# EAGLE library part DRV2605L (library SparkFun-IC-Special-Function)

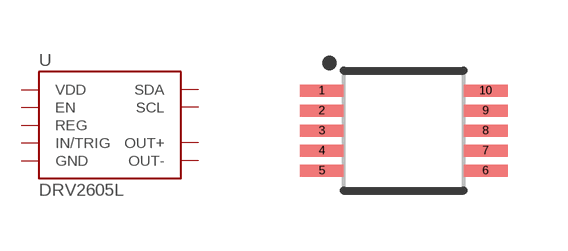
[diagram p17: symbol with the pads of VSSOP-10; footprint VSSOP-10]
Designator prefix U

## DRV2605L (PROD_ID: IC-13504)  [VSSOP-10]
1  REG
2  SCL
3  SDA
4  IN/TRIG
5  EN
6  VDD
7  OUT+
8  GND
9  OUT-
10  VDD

## Footprint VSSOP-10 (pad centres in mm)
smd 1.1 x 0.3: 1 -2.05,1; 2 -2.05,0.5; 3 -2.05,0; 4 -2.05,-0.5; 5 -2.05,-1; 6 2.05,-1; 7 2.05,-0.5; 8 2.05,0; 9 2.05,0.5; 10 2.05,1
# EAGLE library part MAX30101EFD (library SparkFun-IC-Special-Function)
MAX30101 High-Sensitivity Pulse Oximeter and Heart-Rate Sensor The MAX30101 is an integrated pulse oximetry and heart-rate monitor module. It includes internal LEDs, photodetectors, optical elements, and low-noise electronics with ambient light rejection. The MAX30101 provides a complete system solution to ease the design-in process for mobile and wearable devices. The MAX30101 operates on a single 1.8V power supply and a separate 5.0V power supply for the internal LEDs. Communication is through a standard I2C-compatible interface. The module can be shut down through software with zero standby current, allowing the power rails to remain powered at all times

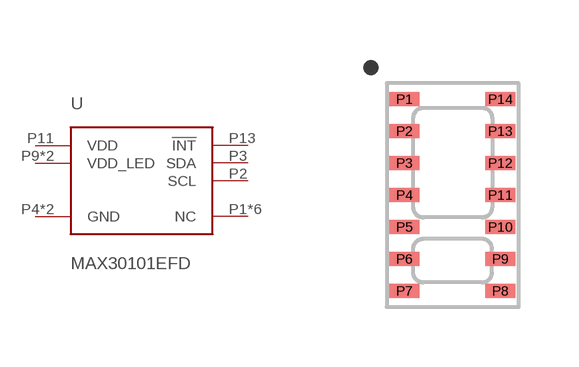
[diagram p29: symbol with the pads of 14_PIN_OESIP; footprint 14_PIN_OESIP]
Designator prefix U

## MAX30101EFD (PROD_ID: IC-14270)  [14_PIN_OESIP]
P1  NC  nc
P2  SCL
P3  SDA
P4  GND  pwr
P5  NC  nc
P6  NC  nc
P7  NC  nc
P8  NC  nc
P9  VDD_LED  pwr
P10  VDD_LED  pwr
P11  VDD  pwr
P12  GND  pwr
P13  !INT
P14  NC  nc

## Footprint 14_PIN_OESIP (pad centres in mm)
MAX30101 14 Pin OESIP Phycial Characteristics: 3.3 X 5.6 X 1.55 mm 14 pin - 8mm Pitch OESIP
smd 0.75 x 0.35: P1 -1.193,2.409; P2 -1.193,1.609; P3 -1.193,0.809; P4 -1.193,0.009; P5 -1.193,-0.791; P6 -1.193,-1.591; P7 -1.193,-2.391; P8 1.207,-2.391; P9 1.207,-1.591; P10 1.207,-0.791; P11 1.207,0.009; P12 1.207,0.809; P13 1.207,1.609; P14 1.207,2.409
